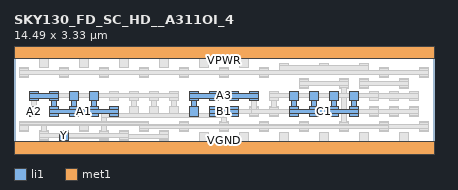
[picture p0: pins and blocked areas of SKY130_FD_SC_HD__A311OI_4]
MACRO SKY130_FD_SC_HD__A311OI_4
 CLASS CORE ;
 FOREIGN SKY130_FD_SC_HD__A311OI_4 0 0 ;
 SIZE 14.49 BY 3.33 ;
 ORIGIN 0 0 ;
 SYMMETRY X Y R90 ;
 SITE unit ;
  PIN VPWR
   DIRECTION INOUT ;
   USE POWER ;
   SHAPE ABUTMENT ;
    PORT
     CLASS CORE ;
       LAYER li1 ;
        RECT 0.00000000 3.09000000 14.49000000 3.57000000 ;
       LAYER met1 ;
        RECT 0.00000000 3.09000000 14.49000000 3.57000000 ;
    END
  END VPWR

  PIN VGND
   DIRECTION INOUT ;
   USE POWER ;
   SHAPE ABUTMENT ;
    PORT
     CLASS CORE ;
       LAYER li1 ;
        RECT 0.00000000 -0.24000000 14.49000000 0.24000000 ;
       LAYER met1 ;
        RECT 0.00000000 -0.24000000 14.49000000 0.24000000 ;
    END
  END VGND

  PIN Y
   DIRECTION INOUT ;
   USE SIGNAL ;
   SHAPE ABUTMENT ;
    PORT
     CLASS CORE ;
       LAYER li1 ;
        RECT 1.56000000 0.26000000 1.89000000 0.59000000 ;
    END
  END Y

  PIN C1
   DIRECTION INOUT ;
   USE SIGNAL ;
   SHAPE ABUTMENT ;
    PORT
     CLASS CORE ;
       LAYER li1 ;
        RECT 9.49500000 1.09500000 9.82500000 1.17500000 ;
        RECT 10.18500000 1.09500000 10.51500000 1.17500000 ;
        RECT 10.87500000 1.09500000 11.20500000 1.17500000 ;
        RECT 11.56500000 1.09500000 11.89500000 1.17500000 ;
        RECT 9.49500000 1.17500000 11.89500000 1.34500000 ;
        RECT 9.49500000 1.34500000 9.82500000 1.42500000 ;
        RECT 10.18500000 1.34500000 10.51500000 1.42500000 ;
        RECT 10.87500000 1.34500000 11.20500000 1.42500000 ;
        RECT 11.56500000 1.34500000 11.89500000 1.42500000 ;
        RECT 9.57500000 1.42500000 9.74500000 1.63500000 ;
        RECT 10.26500000 1.42500000 10.43500000 1.63500000 ;
        RECT 10.95500000 1.42500000 11.12500000 1.63500000 ;
        RECT 11.64500000 1.42500000 11.81500000 1.63500000 ;
        RECT 9.49500000 1.63500000 9.82500000 1.96500000 ;
        RECT 10.18500000 1.63500000 10.51500000 1.96500000 ;
        RECT 10.87500000 1.63500000 11.20500000 1.96500000 ;
        RECT 11.56500000 1.63500000 11.89500000 1.96500000 ;
    END
  END C1

  PIN B1
   DIRECTION INOUT ;
   USE SIGNAL ;
   SHAPE ABUTMENT ;
    PORT
     CLASS CORE ;
       LAYER li1 ;
        RECT 6.73500000 1.09500000 7.06500000 1.17500000 ;
        RECT 7.42500000 1.09500000 7.75500000 1.17500000 ;
        RECT 6.73500000 1.17500000 7.75500000 1.34500000 ;
        RECT 6.73500000 1.34500000 7.06500000 1.42500000 ;
        RECT 7.42500000 1.34500000 7.75500000 1.42500000 ;
    END
  END B1

  PIN A3
   DIRECTION INOUT ;
   USE SIGNAL ;
   SHAPE ABUTMENT ;
    PORT
     CLASS CORE ;
       LAYER li1 ;
        RECT 6.04500000 1.09500000 6.37500000 1.42500000 ;
        RECT 6.12500000 1.42500000 6.29500000 1.63500000 ;
        RECT 6.04500000 1.63500000 6.37500000 1.71500000 ;
        RECT 6.73500000 1.63500000 7.06500000 1.71500000 ;
        RECT 7.42500000 1.63500000 7.75500000 1.71500000 ;
        RECT 8.11500000 1.63500000 8.44500000 1.71500000 ;
        RECT 6.04500000 1.71500000 8.44500000 1.88500000 ;
        RECT 6.04500000 1.88500000 6.37500000 1.96500000 ;
        RECT 6.73500000 1.88500000 7.06500000 1.96500000 ;
        RECT 7.42500000 1.88500000 7.75500000 1.96500000 ;
        RECT 8.11500000 1.88500000 8.44500000 1.96500000 ;
    END
  END A3

  PIN A1
   DIRECTION INOUT ;
   USE SIGNAL ;
   SHAPE ABUTMENT ;
    PORT
     CLASS CORE ;
       LAYER li1 ;
        RECT 1.21500000 1.09500000 1.54500000 1.17500000 ;
        RECT 1.90500000 1.09500000 2.23500000 1.17500000 ;
        RECT 2.59500000 1.09500000 2.92500000 1.17500000 ;
        RECT 3.28500000 1.09500000 3.61500000 1.17500000 ;
        RECT 1.21500000 1.17500000 3.61500000 1.34500000 ;
        RECT 1.21500000 1.34500000 1.54500000 1.42500000 ;
        RECT 1.90500000 1.34500000 2.23500000 1.42500000 ;
        RECT 2.59500000 1.34500000 2.92500000 1.42500000 ;
        RECT 3.28500000 1.34500000 3.61500000 1.42500000 ;
        RECT 1.29500000 1.42500000 1.46500000 1.63500000 ;
        RECT 1.98500000 1.42500000 2.15500000 1.63500000 ;
        RECT 2.67500000 1.42500000 2.84500000 1.63500000 ;
        RECT 0.52500000 1.63500000 0.85500000 1.71500000 ;
        RECT 1.21500000 1.63500000 1.54500000 1.71500000 ;
        RECT 0.52500000 1.71500000 1.54500000 1.88500000 ;
        RECT 0.52500000 1.88500000 0.85500000 1.96500000 ;
        RECT 1.21500000 1.88500000 1.54500000 1.96500000 ;
        RECT 1.90500000 1.63500000 2.23500000 1.96500000 ;
        RECT 2.59500000 1.63500000 2.92500000 1.96500000 ;
    END
  END A1

  PIN A2
   DIRECTION INOUT ;
   USE SIGNAL ;
   SHAPE ABUTMENT ;
    PORT
     CLASS CORE ;
       LAYER li1 ;
        RECT 0.52500000 1.09500000 0.85500000 1.42500000 ;
    END
  END A2

 OBS
    LAYER polycont ;
     RECT 0.60500000 1.17500000 0.77500000 1.34500000 ;
     RECT 4.05500000 1.17500000 4.22500000 1.34500000 ;
     RECT 4.74500000 1.17500000 4.91500000 1.34500000 ;
     RECT 5.43500000 1.17500000 5.60500000 1.34500000 ;
     RECT 3.36500000 1.71500000 3.53500000 1.88500000 ;
     RECT 4.05500000 1.71500000 4.22500000 1.88500000 ;
     RECT 4.74500000 1.71500000 4.91500000 1.88500000 ;
     RECT 5.43500000 1.71500000 5.60500000 1.88500000 ;
     RECT 1.29500000 1.17500000 1.46500000 1.34500000 ;
     RECT 1.98500000 1.17500000 2.15500000 1.34500000 ;
     RECT 2.67500000 1.17500000 2.84500000 1.34500000 ;
     RECT 3.36500000 1.17500000 3.53500000 1.34500000 ;
     RECT 0.60500000 1.71500000 0.77500000 1.88500000 ;
     RECT 1.29500000 1.71500000 1.46500000 1.88500000 ;
     RECT 1.98500000 1.71500000 2.15500000 1.88500000 ;
     RECT 2.67500000 1.71500000 2.84500000 1.88500000 ;
     RECT 6.12500000 1.17500000 6.29500000 1.34500000 ;
     RECT 12.33500000 1.17500000 12.50500000 1.34500000 ;
     RECT 13.02500000 1.17500000 13.19500000 1.34500000 ;
     RECT 13.71500000 1.17500000 13.88500000 1.34500000 ;
     RECT 6.12500000 1.71500000 6.29500000 1.88500000 ;
     RECT 6.81500000 1.71500000 6.98500000 1.88500000 ;
     RECT 7.50500000 1.71500000 7.67500000 1.88500000 ;
     RECT 8.19500000 1.71500000 8.36500000 1.88500000 ;
     RECT 9.57500000 1.17500000 9.74500000 1.34500000 ;
     RECT 10.26500000 1.17500000 10.43500000 1.34500000 ;
     RECT 10.95500000 1.17500000 11.12500000 1.34500000 ;
     RECT 11.64500000 1.17500000 11.81500000 1.34500000 ;
     RECT 9.57500000 1.71500000 9.74500000 1.88500000 ;
     RECT 10.26500000 1.71500000 10.43500000 1.88500000 ;
     RECT 10.95500000 1.71500000 11.12500000 1.88500000 ;
     RECT 11.64500000 1.71500000 11.81500000 1.88500000 ;
     RECT 6.81500000 1.17500000 6.98500000 1.34500000 ;
     RECT 7.50500000 1.17500000 7.67500000 1.34500000 ;
     RECT 8.19500000 1.17500000 8.36500000 1.34500000 ;
     RECT 8.88500000 1.17500000 9.05500000 1.34500000 ;
     RECT 8.88500000 1.71500000 9.05500000 1.88500000 ;
     RECT 12.33500000 1.71500000 12.50500000 1.88500000 ;
     RECT 13.02500000 1.71500000 13.19500000 1.88500000 ;
     RECT 13.71500000 1.71500000 13.88500000 1.88500000 ;

    LAYER pdiffc ;
     RECT 9.92000000 2.15000000 10.09000000 2.32000000 ;
     RECT 11.30000000 2.15000000 11.47000000 2.32000000 ;
     RECT 0.95000000 2.86000000 1.12000000 3.03000000 ;
     RECT 2.33000000 2.86000000 2.50000000 3.03000000 ;
     RECT 3.71000000 2.86000000 3.88000000 3.03000000 ;
     RECT 5.09000000 2.86000000 5.26000000 3.03000000 ;
     RECT 6.47000000 2.86000000 6.64000000 3.03000000 ;
     RECT 7.85000000 2.86000000 8.02000000 3.03000000 ;
     RECT 11.99000000 2.15000000 12.16000000 2.32000000 ;
     RECT 13.37000000 2.15000000 13.54000000 2.32000000 ;
     RECT 9.23000000 2.66000000 9.40000000 2.83000000 ;
     RECT 10.61000000 2.66000000 10.78000000 2.83000000 ;
     RECT 11.99000000 2.66000000 12.16000000 2.83000000 ;
     RECT 0.26000000 2.52500000 0.43000000 2.69500000 ;
     RECT 1.64000000 2.52500000 1.81000000 2.69500000 ;
     RECT 3.02000000 2.52500000 3.19000000 2.69500000 ;
     RECT 4.40000000 2.52500000 4.57000000 2.69500000 ;
     RECT 5.78000000 2.52500000 5.95000000 2.69500000 ;
     RECT 7.16000000 2.52500000 7.33000000 2.69500000 ;
     RECT 8.54000000 2.52500000 8.71000000 2.69500000 ;
     RECT 12.68000000 2.52500000 12.85000000 2.69500000 ;
     RECT 14.06000000 2.52500000 14.23000000 2.69500000 ;

    LAYER ndiffc ;
     RECT 1.64000000 0.34000000 1.81000000 0.51000000 ;
     RECT 3.02000000 0.34000000 3.19000000 0.51000000 ;
     RECT 7.16000000 0.66000000 7.33000000 0.83000000 ;
     RECT 8.54000000 0.66000000 8.71000000 0.83000000 ;
     RECT 9.92000000 0.66000000 10.09000000 0.83000000 ;
     RECT 11.30000000 0.66000000 11.47000000 0.83000000 ;
     RECT 0.95000000 0.34000000 1.12000000 0.51000000 ;
     RECT 3.71000000 0.34000000 3.88000000 0.51000000 ;
     RECT 5.09000000 0.34000000 5.26000000 0.51000000 ;
     RECT 2.33000000 0.66000000 2.50000000 0.83000000 ;
     RECT 6.47000000 0.30000000 6.64000000 0.47000000 ;
     RECT 7.85000000 0.30000000 8.02000000 0.47000000 ;
     RECT 9.23000000 0.30000000 9.40000000 0.47000000 ;
     RECT 10.61000000 0.30000000 10.78000000 0.47000000 ;
     RECT 11.99000000 0.30000000 12.16000000 0.47000000 ;
     RECT 13.37000000 0.30000000 13.54000000 0.47000000 ;
     RECT 0.26000000 0.66000000 0.43000000 0.83000000 ;
     RECT 4.40000000 0.66000000 4.57000000 0.83000000 ;
     RECT 5.78000000 0.66000000 5.95000000 0.83000000 ;
     RECT 12.68000000 0.66000000 12.85000000 0.83000000 ;
     RECT 14.06000000 0.66000000 14.23000000 0.83000000 ;

    LAYER li1 ;
     RECT 7.08000000 0.58000000 7.41000000 0.91000000 ;
     RECT 3.28500000 1.63500000 3.61500000 1.96500000 ;
     RECT 3.97500000 1.63500000 4.30500000 1.96500000 ;
     RECT 4.66500000 1.63500000 4.99500000 1.96500000 ;
     RECT 5.35500000 1.63500000 5.68500000 1.96500000 ;
     RECT 0.00000000 3.09000000 14.49000000 3.57000000 ;
     RECT 0.52500000 1.63500000 0.85500000 1.71500000 ;
     RECT 1.21500000 1.63500000 1.54500000 1.71500000 ;
     RECT 1.90500000 1.63500000 2.23500000 1.96500000 ;
     RECT 2.59500000 1.63500000 2.92500000 1.96500000 ;
     RECT 7.08000000 2.44500000 7.41000000 2.77500000 ;
     RECT 0.00000000 -0.24000000 14.49000000 0.24000000 ;
     RECT 6.04500000 1.63500000 6.37500000 1.71500000 ;
     RECT 6.73500000 1.63500000 7.06500000 1.71500000 ;
     RECT 7.42500000 1.63500000 7.75500000 1.71500000 ;
     RECT 8.11500000 1.63500000 8.44500000 1.71500000 ;
     RECT 6.04500000 1.71500000 8.44500000 1.88500000 ;
     RECT 9.49500000 1.63500000 9.82500000 1.96500000 ;
     RECT 10.18500000 1.63500000 10.51500000 1.96500000 ;
     RECT 10.87500000 1.63500000 11.20500000 1.96500000 ;
     RECT 11.56500000 1.63500000 11.89500000 1.96500000 ;
     RECT 6.73500000 1.17500000 7.75500000 1.34500000 ;
     RECT 8.80500000 1.63500000 9.13500000 1.96500000 ;
     RECT 12.25500000 1.63500000 12.58500000 1.71500000 ;
     RECT 12.94500000 1.63500000 13.27500000 1.71500000 ;
     RECT 13.63500000 1.63500000 13.96500000 1.71500000 ;
     RECT 9.84000000 2.07000000 10.17000000 2.40000000 ;
     RECT 11.22000000 2.07000000 11.55000000 2.40000000 ;
     RECT 11.91000000 2.07000000 12.24000000 2.40000000 ;
     RECT 13.29000000 2.07000000 13.62000000 2.40000000 ;
     RECT 9.15000000 2.58000000 9.48000000 2.66000000 ;
     RECT 10.53000000 2.58000000 10.86000000 2.66000000 ;
     RECT 7.42500000 1.88500000 7.75500000 1.96500000 ;
     RECT 8.11500000 1.88500000 8.44500000 1.96500000 ;
     RECT 11.91000000 2.58000000 12.24000000 2.66000000 ;
     RECT 9.15000000 2.66000000 12.24000000 2.83000000 ;
     RECT 9.15000000 2.83000000 9.48000000 2.91000000 ;
     RECT 10.53000000 2.83000000 10.86000000 2.91000000 ;
     RECT 11.91000000 2.83000000 12.24000000 2.91000000 ;
     RECT 7.77000000 2.78000000 8.10000000 3.09000000 ;
     RECT 8.46000000 2.44500000 8.79000000 2.77500000 ;
     RECT 12.60000000 2.44500000 12.93000000 2.77500000 ;
     RECT 13.98000000 2.44500000 14.31000000 2.77500000 ;
     RECT 12.25500000 1.71500000 13.96500000 1.88500000 ;
     RECT 12.25500000 1.88500000 12.58500000 1.96500000 ;
     RECT 12.94500000 1.88500000 13.27500000 1.96500000 ;
     RECT 13.63500000 1.88500000 13.96500000 1.96500000 ;
     RECT 2.94000000 2.44500000 3.27000000 2.77500000 ;
     RECT 4.32000000 2.44500000 4.65000000 2.77500000 ;
     RECT 5.70000000 2.44500000 6.03000000 2.77500000 ;
     RECT 3.63000000 2.78000000 3.96000000 3.09000000 ;
     RECT 5.01000000 2.78000000 5.34000000 3.09000000 ;
     RECT 0.52500000 1.71500000 1.54500000 1.88500000 ;
     RECT 0.52500000 1.88500000 0.85500000 1.96500000 ;
     RECT 1.21500000 1.88500000 1.54500000 1.96500000 ;
     RECT 6.39000000 2.78000000 6.72000000 3.09000000 ;
     RECT 0.87000000 2.78000000 1.20000000 3.09000000 ;
     RECT 2.25000000 2.78000000 2.58000000 3.09000000 ;
     RECT 0.18000000 2.44500000 0.51000000 2.77500000 ;
     RECT 1.56000000 2.44500000 1.89000000 2.77500000 ;
     RECT 6.04500000 1.88500000 6.37500000 1.96500000 ;
     RECT 6.73500000 1.88500000 7.06500000 1.96500000 ;
     RECT 3.97500000 1.09500000 4.30500000 1.42500000 ;
     RECT 4.05500000 1.42500000 4.22500000 1.63500000 ;
     RECT 1.56000000 0.26000000 1.89000000 0.59000000 ;
     RECT 6.39000000 0.24000000 6.72000000 0.55000000 ;
     RECT 6.04500000 1.09500000 6.37500000 1.42500000 ;
     RECT 6.12500000 1.42500000 6.29500000 1.63500000 ;
     RECT 4.66500000 1.09500000 4.99500000 1.42500000 ;
     RECT 4.74500000 1.42500000 4.91500000 1.63500000 ;
     RECT 0.87000000 0.26000000 1.20000000 0.59000000 ;
     RECT 3.63000000 0.26000000 3.96000000 0.59000000 ;
     RECT 5.01000000 0.26000000 5.34000000 0.59000000 ;
     RECT 2.25000000 0.58000000 2.58000000 0.91000000 ;
     RECT 0.52500000 1.09500000 0.85500000 1.42500000 ;
     RECT 5.35500000 1.09500000 5.68500000 1.42500000 ;
     RECT 1.21500000 1.09500000 1.54500000 1.17500000 ;
     RECT 1.90500000 1.09500000 2.23500000 1.17500000 ;
     RECT 2.59500000 1.09500000 2.92500000 1.17500000 ;
     RECT 3.28500000 1.09500000 3.61500000 1.17500000 ;
     RECT 1.21500000 1.17500000 3.61500000 1.34500000 ;
     RECT 6.73500000 1.09500000 7.06500000 1.17500000 ;
     RECT 1.21500000 1.34500000 1.54500000 1.42500000 ;
     RECT 6.73500000 1.34500000 7.06500000 1.42500000 ;
     RECT 1.90500000 1.34500000 2.23500000 1.42500000 ;
     RECT 2.59500000 1.34500000 2.92500000 1.42500000 ;
     RECT 3.28500000 1.34500000 3.61500000 1.42500000 ;
     RECT 1.29500000 1.42500000 1.46500000 1.63500000 ;
     RECT 1.98500000 1.42500000 2.15500000 1.63500000 ;
     RECT 2.67500000 1.42500000 2.84500000 1.63500000 ;
     RECT 5.43500000 1.42500000 5.60500000 1.63500000 ;
     RECT 2.94000000 0.26000000 3.27000000 0.59000000 ;
     RECT 0.18000000 0.58000000 0.51000000 0.91000000 ;
     RECT 4.32000000 0.58000000 4.65000000 0.91000000 ;
     RECT 5.70000000 0.58000000 6.03000000 0.91000000 ;
     RECT 10.87500000 1.34500000 11.20500000 1.42500000 ;
     RECT 11.56500000 1.34500000 11.89500000 1.42500000 ;
     RECT 9.57500000 1.42500000 9.74500000 1.63500000 ;
     RECT 10.26500000 1.42500000 10.43500000 1.63500000 ;
     RECT 10.95500000 1.42500000 11.12500000 1.63500000 ;
     RECT 11.64500000 1.42500000 11.81500000 1.63500000 ;
     RECT 8.46000000 0.58000000 8.79000000 0.91000000 ;
     RECT 9.84000000 0.58000000 10.17000000 0.91000000 ;
     RECT 11.22000000 0.58000000 11.55000000 0.91000000 ;
     RECT 7.77000000 0.24000000 8.10000000 0.55000000 ;
     RECT 9.15000000 0.24000000 9.48000000 0.55000000 ;
     RECT 7.42500000 1.09500000 7.75500000 1.17500000 ;
     RECT 10.53000000 0.24000000 10.86000000 0.55000000 ;
     RECT 11.91000000 0.24000000 12.24000000 0.55000000 ;
     RECT 7.42500000 1.34500000 7.75500000 1.42500000 ;
     RECT 8.11500000 1.09500000 8.44500000 1.42500000 ;
     RECT 8.80500000 1.09500000 9.13500000 1.42500000 ;
     RECT 13.29000000 0.24000000 13.62000000 0.55000000 ;
     RECT 12.25500000 1.09500000 12.58500000 1.42500000 ;
     RECT 12.94500000 1.09500000 13.27500000 1.42500000 ;
     RECT 13.63500000 1.09500000 13.96500000 1.42500000 ;
     RECT 9.49500000 1.09500000 9.82500000 1.17500000 ;
     RECT 10.18500000 1.09500000 10.51500000 1.17500000 ;
     RECT 10.87500000 1.09500000 11.20500000 1.17500000 ;
     RECT 11.56500000 1.09500000 11.89500000 1.17500000 ;
     RECT 9.49500000 1.17500000 11.89500000 1.34500000 ;
     RECT 9.49500000 1.34500000 9.82500000 1.42500000 ;
     RECT 10.18500000 1.34500000 10.51500000 1.42500000 ;
     RECT 12.60000000 0.58000000 12.93000000 0.91000000 ;
     RECT 13.98000000 0.58000000 14.31000000 0.91000000 ;

    LAYER viali ;
     RECT 1.64000000 0.34000000 1.81000000 0.51000000 ;
     RECT 3.02000000 0.34000000 3.19000000 0.51000000 ;
     RECT 7.16000000 0.66000000 7.33000000 0.83000000 ;
     RECT 8.54000000 0.66000000 8.71000000 0.83000000 ;
     RECT 9.92000000 0.66000000 10.09000000 0.83000000 ;
     RECT 11.30000000 0.66000000 11.47000000 0.83000000 ;
     RECT 9.92000000 2.15000000 10.09000000 2.32000000 ;
     RECT 11.30000000 2.15000000 11.47000000 2.32000000 ;
     RECT 0.60500000 1.17500000 0.77500000 1.34500000 ;
     RECT 3.36500000 1.71500000 3.53500000 1.88500000 ;
     RECT 4.05500000 1.71500000 4.22500000 1.88500000 ;
     RECT 4.74500000 1.71500000 4.91500000 1.88500000 ;
     RECT 5.43500000 1.71500000 5.60500000 1.88500000 ;
     RECT 7.85000000 3.24500000 8.02000000 3.41500000 ;
     RECT 0.95000000 0.34000000 1.12000000 0.51000000 ;
     RECT 3.71000000 0.34000000 3.88000000 0.51000000 ;
     RECT 5.09000000 0.34000000 5.26000000 0.51000000 ;
     RECT 2.33000000 0.66000000 2.50000000 0.83000000 ;
     RECT 11.99000000 2.15000000 12.16000000 2.32000000 ;
     RECT 13.37000000 2.15000000 13.54000000 2.32000000 ;
     RECT 0.26000000 2.52500000 0.43000000 2.69500000 ;
     RECT 1.64000000 2.52500000 1.81000000 2.69500000 ;
     RECT 3.02000000 2.52500000 3.19000000 2.69500000 ;
     RECT 4.40000000 2.52500000 4.57000000 2.69500000 ;
     RECT 5.78000000 2.52500000 5.95000000 2.69500000 ;
     RECT 7.16000000 2.52500000 7.33000000 2.69500000 ;
     RECT 8.54000000 2.52500000 8.71000000 2.69500000 ;
     RECT 12.68000000 2.52500000 12.85000000 2.69500000 ;
     RECT 14.06000000 2.52500000 14.23000000 2.69500000 ;
     RECT 9.23000000 -0.08500000 9.40000000 0.08500000 ;
     RECT 12.33500000 1.17500000 12.50500000 1.34500000 ;
     RECT 13.02500000 1.17500000 13.19500000 1.34500000 ;
     RECT 13.71500000 1.17500000 13.88500000 1.34500000 ;
     RECT 8.19500000 1.71500000 8.36500000 1.88500000 ;
     RECT 7.50500000 1.17500000 7.67500000 1.34500000 ;
     RECT 8.19500000 1.17500000 8.36500000 1.34500000 ;
     RECT 8.88500000 1.17500000 9.05500000 1.34500000 ;
     RECT 8.88500000 1.71500000 9.05500000 1.88500000 ;
     RECT 12.33500000 1.71500000 12.50500000 1.88500000 ;
     RECT 0.26000000 0.66000000 0.43000000 0.83000000 ;
     RECT 4.40000000 0.66000000 4.57000000 0.83000000 ;
     RECT 5.78000000 0.66000000 5.95000000 0.83000000 ;
     RECT 12.68000000 0.66000000 12.85000000 0.83000000 ;
     RECT 14.06000000 0.66000000 14.23000000 0.83000000 ;

    LAYER met1 ;
     RECT 1.58000000 0.28000000 1.87000000 0.31500000 ;
     RECT 2.96000000 0.28000000 3.25000000 0.31500000 ;
     RECT 1.58000000 0.31500000 3.25000000 0.45500000 ;
     RECT 1.58000000 0.45500000 1.87000000 0.57000000 ;
     RECT 2.96000000 0.45500000 3.25000000 0.57000000 ;
     RECT 7.10000000 0.60000000 7.39000000 0.67500000 ;
     RECT 8.48000000 0.60000000 8.77000000 0.67500000 ;
     RECT 9.86000000 0.60000000 10.15000000 0.67500000 ;
     RECT 11.24000000 0.60000000 11.53000000 0.67500000 ;
     RECT 7.10000000 0.67500000 11.53000000 0.81500000 ;
     RECT 7.10000000 0.81500000 7.39000000 0.89000000 ;
     RECT 8.48000000 0.81500000 8.77000000 0.89000000 ;
     RECT 9.86000000 0.81500000 10.15000000 0.89000000 ;
     RECT 11.24000000 0.81500000 11.53000000 0.89000000 ;
     RECT 3.03500000 0.57000000 3.17500000 1.05500000 ;
     RECT 7.17500000 0.89000000 7.31500000 1.05500000 ;
     RECT 3.03500000 1.05500000 7.31500000 1.19500000 ;
     RECT 11.31500000 0.89000000 11.45500000 2.09000000 ;
     RECT 9.86000000 2.09000000 10.15000000 2.16500000 ;
     RECT 11.24000000 2.09000000 11.53000000 2.16500000 ;
     RECT 9.86000000 2.16500000 11.53000000 2.30500000 ;
     RECT 9.86000000 2.30500000 10.15000000 2.38000000 ;
     RECT 11.24000000 2.30500000 11.53000000 2.38000000 ;
     RECT 0.54500000 1.11500000 0.83500000 1.40500000 ;
     RECT 0.62000000 1.40500000 0.76000000 1.73000000 ;
     RECT 3.30500000 1.65500000 3.59500000 1.73000000 ;
     RECT 3.99500000 1.65500000 4.28500000 1.73000000 ;
     RECT 4.68500000 1.65500000 4.97500000 1.73000000 ;
     RECT 5.37500000 1.65500000 5.66500000 1.73000000 ;
     RECT 0.62000000 1.73000000 5.66500000 1.87000000 ;
     RECT 3.30500000 1.87000000 3.59500000 1.94500000 ;
     RECT 3.99500000 1.87000000 4.28500000 1.94500000 ;
     RECT 4.68500000 1.87000000 4.97500000 1.94500000 ;
     RECT 5.37500000 1.87000000 5.66500000 1.94500000 ;
     RECT 0.00000000 3.09000000 14.49000000 3.57000000 ;
     RECT 3.65000000 0.28000000 3.94000000 0.31500000 ;
     RECT 5.03000000 0.28000000 5.32000000 0.31500000 ;
     RECT 3.65000000 0.31500000 5.32000000 0.45500000 ;
     RECT 3.65000000 0.45500000 3.94000000 0.57000000 ;
     RECT 5.03000000 0.45500000 5.32000000 0.57000000 ;
     RECT 0.89000000 0.28000000 1.18000000 0.57000000 ;
     RECT 0.96500000 0.57000000 1.10500000 0.78500000 ;
     RECT 2.27000000 0.60000000 2.56000000 0.78500000 ;
     RECT 0.96500000 0.78500000 2.56000000 0.89000000 ;
     RECT 0.96500000 0.89000000 2.48500000 0.92500000 ;
     RECT 11.93000000 2.09000000 12.22000000 2.16500000 ;
     RECT 13.31000000 2.09000000 13.60000000 2.16500000 ;
     RECT 11.93000000 2.16500000 13.60000000 2.30500000 ;
     RECT 11.93000000 2.30500000 12.22000000 2.38000000 ;
     RECT 13.31000000 2.30500000 13.60000000 2.38000000 ;
     RECT 0.20000000 2.46500000 0.49000000 2.54000000 ;
     RECT 1.58000000 2.46500000 1.87000000 2.54000000 ;
     RECT 2.96000000 2.46500000 3.25000000 2.54000000 ;
     RECT 4.34000000 2.46500000 4.63000000 2.54000000 ;
     RECT 5.72000000 2.46500000 6.01000000 2.54000000 ;
     RECT 7.10000000 2.46500000 7.39000000 2.54000000 ;
     RECT 8.48000000 2.46500000 8.77000000 2.54000000 ;
     RECT 12.62000000 2.46500000 12.91000000 2.54000000 ;
     RECT 14.00000000 2.46500000 14.29000000 2.54000000 ;
     RECT 0.20000000 2.54000000 14.29000000 2.68000000 ;
     RECT 0.20000000 2.68000000 0.49000000 2.75500000 ;
     RECT 1.58000000 2.68000000 1.87000000 2.75500000 ;
     RECT 2.96000000 2.68000000 3.25000000 2.75500000 ;
     RECT 4.34000000 2.68000000 4.63000000 2.75500000 ;
     RECT 5.72000000 2.68000000 6.01000000 2.75500000 ;
     RECT 7.10000000 2.68000000 7.39000000 2.75500000 ;
     RECT 8.48000000 2.68000000 8.77000000 2.75500000 ;
     RECT 12.62000000 2.68000000 12.91000000 2.75500000 ;
     RECT 14.00000000 2.68000000 14.29000000 2.75500000 ;
     RECT 0.00000000 -0.24000000 14.49000000 0.24000000 ;
     RECT 12.27500000 1.11500000 12.56500000 1.19000000 ;
     RECT 12.96500000 1.11500000 13.25500000 1.19000000 ;
     RECT 13.65500000 1.11500000 13.94500000 1.19000000 ;
     RECT 12.27500000 1.19000000 13.94500000 1.33000000 ;
     RECT 12.27500000 1.33000000 12.56500000 1.40500000 ;
     RECT 12.96500000 1.33000000 13.25500000 1.40500000 ;
     RECT 13.65500000 1.33000000 13.94500000 1.40500000 ;
     RECT 8.13500000 1.65500000 8.42500000 1.94500000 ;
     RECT 7.44500000 1.11500000 7.73500000 1.19000000 ;
     RECT 8.13500000 1.11500000 8.42500000 1.19000000 ;
     RECT 8.82500000 1.11500000 9.11500000 1.19000000 ;
     RECT 7.44500000 1.19000000 9.11500000 1.33000000 ;
     RECT 7.44500000 1.33000000 7.73500000 1.40500000 ;
     RECT 8.13500000 1.33000000 8.42500000 1.40500000 ;
     RECT 8.82500000 1.33000000 9.11500000 1.40500000 ;
     RECT 8.90000000 1.40500000 9.04000000 1.65500000 ;
     RECT 8.82500000 1.65500000 9.11500000 1.94500000 ;
     RECT 12.27500000 1.65500000 12.56500000 1.94500000 ;
     RECT 0.20000000 0.60000000 0.49000000 0.89000000 ;
     RECT 4.34000000 0.60000000 4.63000000 0.89000000 ;
     RECT 5.72000000 0.60000000 6.01000000 0.89000000 ;
     RECT 12.62000000 0.60000000 12.91000000 0.67500000 ;
     RECT 14.00000000 0.60000000 14.29000000 0.67500000 ;
     RECT 12.62000000 0.67500000 14.29000000 0.81500000 ;
     RECT 12.62000000 0.81500000 12.91000000 0.89000000 ;
     RECT 14.00000000 0.81500000 14.29000000 0.89000000 ;

    LAYER via ;
     RECT 0.95000000 0.34000000 1.12000000 0.51000000 ;
     RECT 3.71000000 0.34000000 3.88000000 0.51000000 ;
     RECT 12.33500000 1.17500000 12.50500000 1.34500000 ;
     RECT 8.19500000 1.71500000 8.36500000 1.88500000 ;
     RECT 8.88500000 1.71500000 9.05500000 1.88500000 ;
     RECT 12.33500000 1.71500000 12.50500000 1.88500000 ;
     RECT 0.26000000 0.66000000 0.43000000 0.83000000 ;
     RECT 4.40000000 0.66000000 4.57000000 0.83000000 ;
     RECT 5.78000000 0.66000000 5.95000000 0.83000000 ;
     RECT 12.68000000 0.66000000 12.85000000 0.83000000 ;

    LAYER met2 ;
     RECT 0.89000000 0.28000000 1.18000000 0.35500000 ;
     RECT 3.65000000 0.28000000 3.94000000 0.35500000 ;
     RECT 0.89000000 0.35500000 3.94000000 0.49500000 ;
     RECT 0.89000000 0.49500000 1.18000000 0.57000000 ;
     RECT 3.65000000 0.49500000 3.94000000 0.57000000 ;
     RECT 12.27500000 1.11500000 12.56500000 1.19000000 ;
     RECT 8.21000000 1.19000000 12.56500000 1.33000000 ;
     RECT 12.27500000 1.33000000 12.56500000 1.40500000 ;
     RECT 8.21000000 1.33000000 8.35000000 1.65500000 ;
     RECT 8.13500000 1.65500000 8.42500000 1.94500000 ;
     RECT 8.82500000 1.65500000 9.11500000 1.73000000 ;
     RECT 12.27500000 1.65500000 12.56500000 1.73000000 ;
     RECT 8.82500000 1.73000000 12.56500000 1.87000000 ;
     RECT 8.82500000 1.87000000 9.11500000 1.94500000 ;
     RECT 12.27500000 1.87000000 12.56500000 1.94500000 ;
     RECT 4.34000000 0.60000000 4.63000000 0.67500000 ;
     RECT 5.72000000 0.60000000 6.01000000 0.67500000 ;
     RECT 12.62000000 0.60000000 12.91000000 0.67500000 ;
     RECT 0.20000000 0.60000000 0.49000000 0.78500000 ;
     RECT 4.34000000 0.67500000 12.91000000 0.78500000 ;
     RECT 0.20000000 0.78500000 12.91000000 0.81500000 ;
     RECT 0.20000000 0.81500000 4.63000000 0.89000000 ;
     RECT 5.72000000 0.81500000 6.01000000 0.89000000 ;
     RECT 12.62000000 0.81500000 12.91000000 0.89000000 ;
     RECT 0.27500000 0.89000000 4.55500000 0.92500000 ;

    LAYER via2 ;


    LAYER met3 ;


 END
END SKY130_FD_SC_HD__A311OI_4
